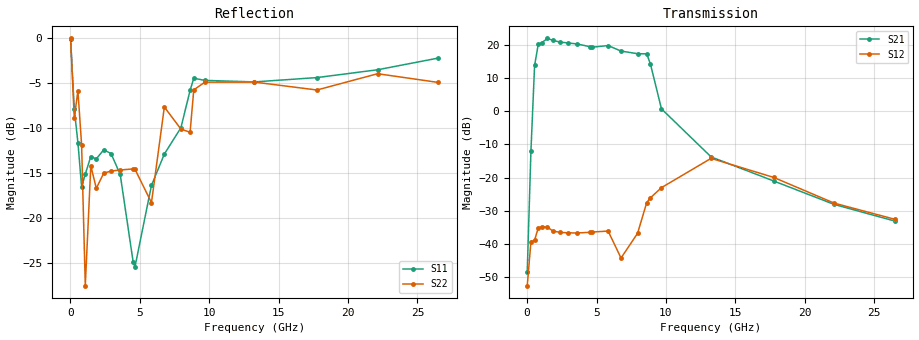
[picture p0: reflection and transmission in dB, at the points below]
!Agilent Technologies,N5242A,MY52422126,A.09.90.01
!Agilent N5242A: A.09.90.01
!Date: Thursday, November 19, 2015 09:07:45
!Correction: S11(Full 2 Port(1,2))
!S21(Full 2 Port(1,2))
!S12(Full 2 Port(1,2))
!S22(Full 2 Port(1,2))
!S2P File: Measurements: S11, S21, S12, S22:
# Hz S  dB  R 50
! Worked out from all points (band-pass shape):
!   201 points, 10 MHz to 26.5 GHz, reference 50 ohm
!   highest |S21| = 21.90 dB at 1.467 GHz (marker M1); lowest = -48.3 dB at 10 MHz (marker M2)
!   |S21| within 3 dB of the highest: 679.6 MHz to 4.938 GHz (4.259 GHz wide, 152 % of centre); 5.241 GHz to 6.441 GHz (1.2 GHz wide, 20.5 % of centre)
!   lowest |S11| = -25.4 dB at 4.646 GHz (marker M3), VSWR 1.11, Z = 54.3 - j3.57 ohm
!   |S11| at or under -10 dB: 376.9 MHz to 7.346 GHz (6.969 GHz wide, 180 % of centre); 7.701 GHz to 7.927 GHz (225.9 MHz wide, 2.89 % of centre)
!   |S22| runs from -29.1 to 0.0 dB; largest |S21 - S12| = 12
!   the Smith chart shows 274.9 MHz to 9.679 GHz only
!   S11 on the Smith chart (normalised r, x): 274.9 MHz: 0.46, -0.25; 539.8 MHz: 0.75, +0.40; 2.394 GHz: 1.55, -0.28; 8.619 GHz: 0.85, -1.09; 9.679 GHz: 0.37, -0.61
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1e7  -0.07 -7.0  -48.31 -45.2  -52.55 50.6  -0.03 -6.2
2.749e8  -7.91 -145.3  -12.09 -98.3  -39.33 -62.4  -8.88 -158.7
5.398e8  -11.62 109.5  13.76 176.3  -38.83 174.0  -5.87 23.4
8.047e8  -16.55 51.1  20.12 73.2  -35.13 76.0  -11.87 -75.4
1.0696e9  -15.11 46.8  20.65 16.8  -34.74 25.7  -27.52 19.0
1.46695e9  -13.17 13.4  21.90 -42.7  -34.95 -23.7  -14.20 -17.1
1.8643e9  -13.42 0.4  21.30 -93.8  -36.12 -51.5  -16.70 -22.3
2.3941e9  -12.42 -20.9  20.76 -145.7  -36.49 -83.7  -15.02 -26.2
2.9239e9  -12.83 -44.3  20.53 166.5  -36.64 -116.7  -14.78 -38.0
3.58615e9  -15.16 -70.8  20.23 108.4  -36.69 -158.1  -14.66 -50.7
4.5133e9  -24.84 -61.9  19.40 28.8  -36.48 143.6  -14.54 -68.9
4.64575e9  -25.45 -37.9  19.23 17.9  -36.41 135.9  -14.57 -74.0
5.8378e9  -16.37 -56.2  19.73 -81.1  -36.11 49.6  -18.29 3.1
6.76495e9  -12.89 -40.2  18.08 -173.0  -44.22 5.5  -7.66 -57.3
7.957e9  -9.97 -65.5  17.28 76.8  -36.80 91.1  -10.11 -136.3
8.61925e9  -5.82 -67.4  17.24 -22.2  -27.51 54.4  -10.47 -6.2
8.88415e9  -4.46 -84.5  14.18 -68.7  -26.10 33.5  -5.76 -49.4
9.67885e9  -4.70 -112.2  0.68 -158.7  -23.04 -6.4  -4.90 -101.2
1.3255e10  -4.87 148.0  -13.78 175.8  -14.22 -176.5  -4.89 159.2
1.77583e10  -4.39 51.3  -21.02 -63.0  -19.95 -55.8  -5.77 55.9
2.212915e10  -3.52 -85.7  -28.10 162.2  -27.71 161.6  -3.96 -86.3
2.65e10  -2.22 -168.5  -33.11 25.1  -32.57 24.7  -4.93 -153.5
